VERSION 5.7 ;
BUSBITCHARS "[]" ;
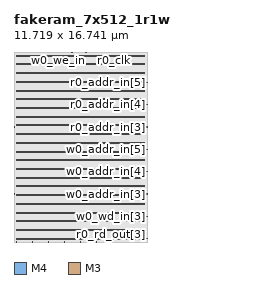
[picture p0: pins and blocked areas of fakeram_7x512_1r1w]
MACRO fakeram_7x512_1r1w
  FOREIGN fakeram_7x512_1r1w 0 0 ;
  SYMMETRY X Y R90 ;
  SIZE 11.719 BY 16.741 ;
  CLASS BLOCK ;
  PIN w0_wd_in[0]
    DIRECTION INPUT ;
    USE SIGNAL ;
    SHAPE ABUTMENT ;
    PORT
      LAYER M4 ;
      RECT 0.000 0.276 0.072 0.300 ;
    END
  END w0_wd_in[0]
  PIN w0_wd_in[1]
    DIRECTION INPUT ;
    USE SIGNAL ;
    SHAPE ABUTMENT ;
    PORT
      LAYER M4 ;
      RECT 0.000 2.244 0.072 2.268 ;
    END
  END w0_wd_in[1]
  PIN w0_wd_in[2]
    DIRECTION INPUT ;
    USE SIGNAL ;
    SHAPE ABUTMENT ;
    PORT
      LAYER M4 ;
      RECT 11.647 0.276 11.719 0.300 ;
    END
  END w0_wd_in[2]
  PIN w0_wd_in[3]
    DIRECTION INPUT ;
    USE SIGNAL ;
    SHAPE ABUTMENT ;
    PORT
      LAYER M4 ;
      RECT 11.647 2.244 11.719 2.268 ;
    END
  END w0_wd_in[3]
  PIN w0_wd_in[4]
    DIRECTION INPUT ;
    USE SIGNAL ;
    SHAPE ABUTMENT ;
    PORT
      LAYER M3 ;
      RECT 0.207 0.000 0.225 0.054 ;
    END
  END w0_wd_in[4]
  PIN w0_wd_in[5]
    DIRECTION INPUT ;
    USE SIGNAL ;
    SHAPE ABUTMENT ;
    PORT
      LAYER M3 ;
      RECT 1.611 0.000 1.629 0.054 ;
    END
  END w0_wd_in[5]
  PIN w0_wd_in[6]
    DIRECTION INPUT ;
    USE SIGNAL ;
    SHAPE ABUTMENT ;
    PORT
      LAYER M3 ;
      RECT 3.015 0.000 3.033 0.054 ;
    END
  END w0_wd_in[6]
  PIN r0_rd_out[0]
    DIRECTION OUTPUT ;
    USE SIGNAL ;
    SHAPE ABUTMENT ;
    PORT
      LAYER M3 ;
      RECT 4.419 0.000 4.437 0.054 ;
    END
  END r0_rd_out[0]
  PIN r0_rd_out[1]
    DIRECTION OUTPUT ;
    USE SIGNAL ;
    SHAPE ABUTMENT ;
    PORT
      LAYER M3 ;
      RECT 5.823 0.000 5.841 0.054 ;
    END
  END r0_rd_out[1]
  PIN r0_rd_out[2]
    DIRECTION OUTPUT ;
    USE SIGNAL ;
    SHAPE ABUTMENT ;
    PORT
      LAYER M3 ;
      RECT 7.227 0.000 7.245 0.054 ;
    END
  END r0_rd_out[2]
  PIN r0_rd_out[3]
    DIRECTION OUTPUT ;
    USE SIGNAL ;
    SHAPE ABUTMENT ;
    PORT
      LAYER M3 ;
      RECT 8.631 0.000 8.649 0.054 ;
    END
  END r0_rd_out[3]
  PIN r0_rd_out[4]
    DIRECTION OUTPUT ;
    USE SIGNAL ;
    SHAPE ABUTMENT ;
    PORT
      LAYER M3 ;
      RECT 0.207 16.687 0.225 16.741 ;
    END
  END r0_rd_out[4]
  PIN r0_rd_out[5]
    DIRECTION OUTPUT ;
    USE SIGNAL ;
    SHAPE ABUTMENT ;
    PORT
      LAYER M3 ;
      RECT 1.431 16.687 1.449 16.741 ;
    END
  END r0_rd_out[5]
  PIN r0_rd_out[6]
    DIRECTION OUTPUT ;
    USE SIGNAL ;
    SHAPE ABUTMENT ;
    PORT
      LAYER M3 ;
      RECT 2.655 16.687 2.673 16.741 ;
    END
  END r0_rd_out[6]
  PIN w0_addr_in[0]
    DIRECTION INPUT ;
    USE SIGNAL ;
    SHAPE ABUTMENT ;
    PORT
      LAYER M4 ;
      RECT 0.000 4.212 0.072 4.236 ;
    END
  END w0_addr_in[0]
  PIN w0_addr_in[1]
    DIRECTION INPUT ;
    USE SIGNAL ;
    SHAPE ABUTMENT ;
    PORT
      LAYER M4 ;
      RECT 0.000 6.180 0.072 6.204 ;
    END
  END w0_addr_in[1]
  PIN w0_addr_in[2]
    DIRECTION INPUT ;
    USE SIGNAL ;
    SHAPE ABUTMENT ;
    PORT
      LAYER M4 ;
      RECT 0.000 8.148 0.072 8.172 ;
    END
  END w0_addr_in[2]
  PIN w0_addr_in[3]
    DIRECTION INPUT ;
    USE SIGNAL ;
    SHAPE ABUTMENT ;
    PORT
      LAYER M4 ;
      RECT 11.647 4.212 11.719 4.236 ;
    END
  END w0_addr_in[3]
  PIN w0_addr_in[4]
    DIRECTION INPUT ;
    USE SIGNAL ;
    SHAPE ABUTMENT ;
    PORT
      LAYER M4 ;
      RECT 11.647 6.180 11.719 6.204 ;
    END
  END w0_addr_in[4]
  PIN w0_addr_in[5]
    DIRECTION INPUT ;
    USE SIGNAL ;
    SHAPE ABUTMENT ;
    PORT
      LAYER M4 ;
      RECT 11.647 8.148 11.719 8.172 ;
    END
  END w0_addr_in[5]
  PIN r0_addr_in[0]
    DIRECTION INPUT ;
    USE SIGNAL ;
    SHAPE ABUTMENT ;
    PORT
      LAYER M4 ;
      RECT 0.000 10.116 0.072 10.140 ;
    END
  END r0_addr_in[0]
  PIN r0_addr_in[1]
    DIRECTION INPUT ;
    USE SIGNAL ;
    SHAPE ABUTMENT ;
    PORT
      LAYER M4 ;
      RECT 0.000 12.084 0.072 12.108 ;
    END
  END r0_addr_in[1]
  PIN r0_addr_in[2]
    DIRECTION INPUT ;
    USE SIGNAL ;
    SHAPE ABUTMENT ;
    PORT
      LAYER M4 ;
      RECT 0.000 14.052 0.072 14.076 ;
    END
  END r0_addr_in[2]
  PIN r0_addr_in[3]
    DIRECTION INPUT ;
    USE SIGNAL ;
    SHAPE ABUTMENT ;
    PORT
      LAYER M4 ;
      RECT 11.647 10.116 11.719 10.140 ;
    END
  END r0_addr_in[3]
  PIN r0_addr_in[4]
    DIRECTION INPUT ;
    USE SIGNAL ;
    SHAPE ABUTMENT ;
    PORT
      LAYER M4 ;
      RECT 11.647 12.084 11.719 12.108 ;
    END
  END r0_addr_in[4]
  PIN r0_addr_in[5]
    DIRECTION INPUT ;
    USE SIGNAL ;
    SHAPE ABUTMENT ;
    PORT
      LAYER M4 ;
      RECT 11.647 14.052 11.719 14.076 ;
    END
  END r0_addr_in[5]
  PIN w0_we_in
    DIRECTION INPUT ;
    USE SIGNAL ;
    SHAPE ABUTMENT ;
    PORT
      LAYER M3 ;
      RECT 3.879 16.687 3.897 16.741 ;
    END
  END w0_we_in
  PIN w0_ce_in
    DIRECTION INPUT ;
    USE SIGNAL ;
    SHAPE ABUTMENT ;
    PORT
      LAYER M3 ;
      RECT 5.103 16.687 5.121 16.741 ;
    END
  END w0_ce_in
  PIN w0_clk
    DIRECTION INPUT ;
    USE SIGNAL ;
    SHAPE ABUTMENT ;
    PORT
      LAYER M3 ;
      RECT 6.327 16.687 6.345 16.741 ;
    END
  END w0_clk
  PIN r0_ce_in
    DIRECTION INPUT ;
    USE SIGNAL ;
    SHAPE ABUTMENT ;
    PORT
      LAYER M3 ;
      RECT 7.551 16.687 7.569 16.741 ;
    END
  END r0_ce_in
  PIN r0_clk
    DIRECTION INPUT ;
    USE SIGNAL ;
    SHAPE ABUTMENT ;
    PORT
      LAYER M3 ;
      RECT 8.775 16.687 8.793 16.741 ;
    END
  END r0_clk
  PIN VSS
    DIRECTION INOUT ;
    USE GROUND ;
    PORT
      LAYER M4 ;
      RECT 0.216 0.240 11.503 0.336 ;
      RECT 0.216 1.008 11.503 1.104 ;
      RECT 0.216 1.776 11.503 1.872 ;
      RECT 0.216 2.544 11.503 2.640 ;
      RECT 0.216 3.312 11.503 3.408 ;
      RECT 0.216 4.080 11.503 4.176 ;
      RECT 0.216 4.848 11.503 4.944 ;
      RECT 0.216 5.616 11.503 5.712 ;
      RECT 0.216 6.384 11.503 6.480 ;
      RECT 0.216 7.152 11.503 7.248 ;
      RECT 0.216 7.920 11.503 8.016 ;
      RECT 0.216 8.688 11.503 8.784 ;
      RECT 0.216 9.456 11.503 9.552 ;
      RECT 0.216 10.224 11.503 10.320 ;
      RECT 0.216 10.992 11.503 11.088 ;
      RECT 0.216 11.760 11.503 11.856 ;
      RECT 0.216 12.528 11.503 12.624 ;
      RECT 0.216 13.296 11.503 13.392 ;
      RECT 0.216 14.064 11.503 14.160 ;
      RECT 0.216 14.832 11.503 14.928 ;
      RECT 0.216 15.600 11.503 15.696 ;
      RECT 0.216 16.368 11.503 16.464 ;
    END
  END VSS
  PIN VDD
    DIRECTION INOUT ;
    USE POWER ;
    PORT
      LAYER M4 ;
      RECT 0.216 0.240 11.503 0.336 ;
      RECT 0.216 1.008 11.503 1.104 ;
      RECT 0.216 1.776 11.503 1.872 ;
      RECT 0.216 2.544 11.503 2.640 ;
      RECT 0.216 3.312 11.503 3.408 ;
      RECT 0.216 4.080 11.503 4.176 ;
      RECT 0.216 4.848 11.503 4.944 ;
      RECT 0.216 5.616 11.503 5.712 ;
      RECT 0.216 6.384 11.503 6.480 ;
      RECT 0.216 7.152 11.503 7.248 ;
      RECT 0.216 7.920 11.503 8.016 ;
      RECT 0.216 8.688 11.503 8.784 ;
      RECT 0.216 9.456 11.503 9.552 ;
      RECT 0.216 10.224 11.503 10.320 ;
      RECT 0.216 10.992 11.503 11.088 ;
      RECT 0.216 11.760 11.503 11.856 ;
      RECT 0.216 12.528 11.503 12.624 ;
      RECT 0.216 13.296 11.503 13.392 ;
      RECT 0.216 14.064 11.503 14.160 ;
      RECT 0.216 14.832 11.503 14.928 ;
      RECT 0.216 15.600 11.503 15.696 ;
      RECT 0.216 16.368 11.503 16.464 ;
    END
  END VDD
  OBS
    LAYER M1 ;
    RECT 0 0 11.719 16.741 ;
    LAYER M2 ;
    RECT 0 0 11.719 16.741 ;
    LAYER M3 ;
    RECT 0 0 11.719 16.741 ;
    LAYER M4 ;
    RECT 0 0 11.719 16.741 ;
  END
END fakeram_7x512_1r1w

END LIBRARY
